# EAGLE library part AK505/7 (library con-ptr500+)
CONNECTOR

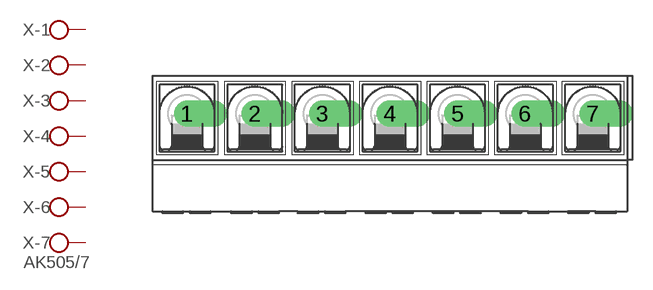
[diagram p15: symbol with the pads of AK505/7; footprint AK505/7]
Designator prefix X; gates -1=KL -2=KL -3=KL -4=KL -5=KL -6=KL -7=KLV

## AK505/7  [AK505/7]
1  -1:KL  pas
2  -2:KL  pas
3  -3:KL  pas
4  -4:KL  pas
5  -5:KL  pas
6  -6:KL  pas
7  -7:KL  pas

## Footprint AK505/7 (pad centres in mm)
CONNECTOR
drill 1.321 offset: 1 -15.037,0; 2 -10.008,0; 3 -5.004,0; 4 0,0; 5 5.004,0; 6 10.008,0; 7 15.037,0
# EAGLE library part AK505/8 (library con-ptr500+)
CONNECTOR

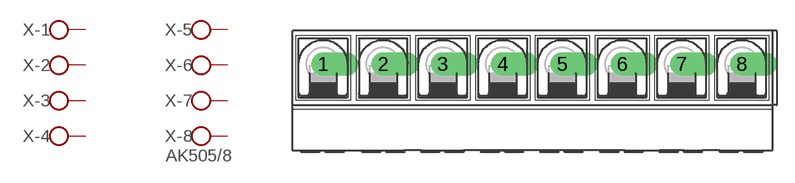
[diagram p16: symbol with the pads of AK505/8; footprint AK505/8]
Designator prefix X; gates -1=KL -2=KL -3=KL -4=KL -5=KL -6=KL -7=KL -8=KLV

## AK505/8  [AK505/8]
1  -1:KL  pas
2  -2:KL  pas
3  -3:KL  pas
4  -4:KL  pas
5  -5:KL  pas
6  -6:KL  pas
7  -7:KL  pas
8  -8:KL  pas

## Footprint AK505/8 (pad centres in mm)
CONNECTOR
drill 1.321 offset: 1 -17.526,0; 2 -12.497,0; 3 -7.518,0; 4 -2.489,0; 5 2.489,0; 6 7.518,0; 7 12.497,0; 8 17.526,0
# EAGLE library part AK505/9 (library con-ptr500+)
CONNECTOR

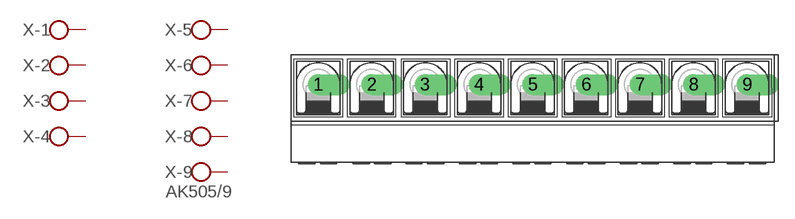
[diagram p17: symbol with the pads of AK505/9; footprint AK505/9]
Designator prefix X; gates -1=KL -2=KL -3=KL -4=KL -5=KL -6=KL -7=KL -8=KL -9=KLV

## AK505/9  [AK505/9]
1  -1:KL  pas
2  -2:KL  pas
3  -3:KL  pas
4  -4:KL  pas
5  -5:KL  pas
6  -6:KL  pas
7  -7:KL  pas
8  -8:KL  pas
9  -9:KL  pas

## Footprint AK505/9 (pad centres in mm)
CONNECTOR
drill 1.321 offset: 1 -20.015,0; 2 -15.011,0; 3 -10.033,0; 4 -5.004,0; 5 0,0; 6 5.004,0; 7 10.033,0; 8 15.011,0; 9 20.015,0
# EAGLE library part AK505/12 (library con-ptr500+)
CONNECTOR

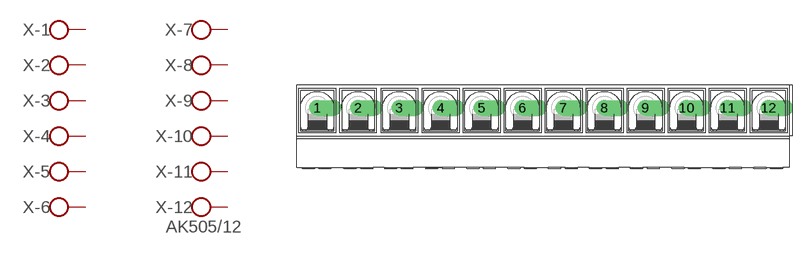
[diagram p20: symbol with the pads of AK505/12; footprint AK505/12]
Designator prefix X; gates -1=KL -2=KL -3=KL -4=KL -5=KL -6=KL -7=KL -8=KL -9=KL -10=KL -11=KL -12=KLV

## AK505/12  [AK505/12]
1  -1:KL  pas
2  -2:KL  pas
3  -3:KL  pas
4  -4:KL  pas
5  -5:KL  pas
6  -6:KL  pas
7  -7:KL  pas
8  -8:KL  pas
9  -9:KL  pas
10  -10:KL  pas
11  -11:KL  pas
12  -12:KL  pas

## Footprint AK505/12 (pad centres in mm)
CONNECTOR
drill 1.321 offset: 1 -27.534,0; 2 -22.53,0; 3 -17.526,0; 4 -12.497,0; 5 -7.493,0; 6 -2.489,0; 7 2.489,0; 8 7.493,0; 9 12.497,0; 10 17.526,0; 11 22.53,0; 12 27.534,0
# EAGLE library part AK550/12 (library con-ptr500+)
CONNECTOR

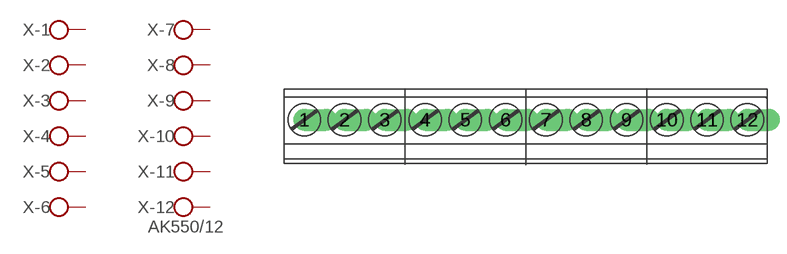
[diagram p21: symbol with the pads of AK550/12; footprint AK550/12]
Designator prefix X; gates -1=KL -2=KL -3=KL -4=KL -5=KL -6=KL -7=KL -8=KL -9=KL -10=KL -11=KL -12=KLV

## AK550/12  [AK550/12]
1  -1:KL  pas
2  -2:KL  pas
3  -3:KL  pas
4  -4:KL  pas
5  -5:KL  pas
6  -6:KL  pas
7  -7:KL  pas
8  -8:KL  pas
9  -9:KL  pas
10  -10:KL  pas
11  -11:KL  pas
12  -12:KL  pas

## Footprint AK550/12 (pad centres in mm)
CONNECTOR
drill 1.27 offset: 1 -19.25,0; 2 -15.75,0; 3 -12.25,0; 4 -8.75,0; 5 -5.25,0; 6 -1.75,0; 7 1.75,0; 8 5.25,0; 9 8.75,0; 10 12.25,0; 11 15.75,0; 12 19.25,0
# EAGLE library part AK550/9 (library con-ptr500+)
CONNECTOR

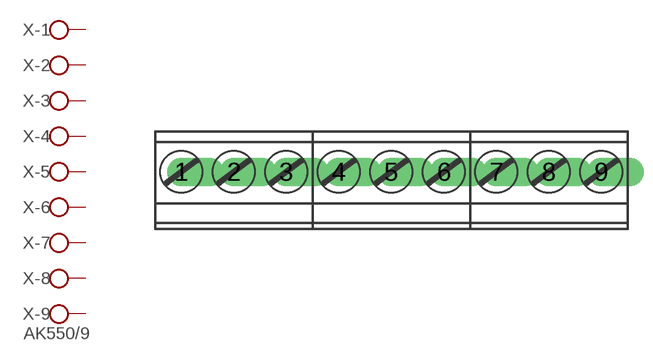
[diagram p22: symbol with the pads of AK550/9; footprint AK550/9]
Designator prefix X; gates -1=KL -2=KL -3=KL -4=KL -5=KL -6=KL -7=KL -8=KL -9=KLV

## AK550/9  [AK550/9]
1  -1:KL  pas
2  -2:KL  pas
3  -3:KL  pas
4  -4:KL  pas
5  -5:KL  pas
6  -6:KL  pas
7  -7:KL  pas
8  -8:KL  pas
9  -9:KL  pas

## Footprint AK550/9 (pad centres in mm)
CONNECTOR
drill 1.27 offset: 1 -14,0; 2 -10.5,0; 3 -7,0; 4 -3.5,0; 5 0,0; 6 3.5,0; 7 7,0; 8 10.5,0; 9 14,0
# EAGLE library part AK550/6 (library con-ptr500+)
CONNECTOR

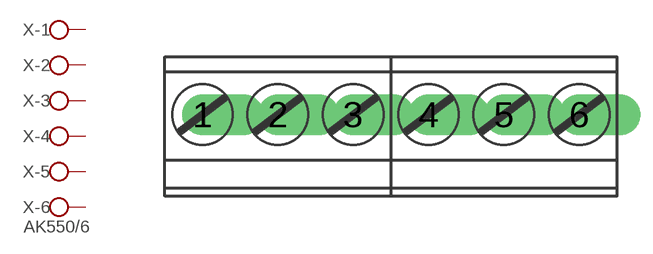
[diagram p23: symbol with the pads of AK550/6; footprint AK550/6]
Designator prefix X; gates -1=KL -2=KL -3=KL -4=KL -5=KL -6=KLV

## AK550/6  [AK550/6]
1  -1:KL  pas
2  -2:KL  pas
3  -3:KL  pas
4  -4:KL  pas
5  -5:KL  pas
6  -6:KL  pas

## Footprint AK550/6 (pad centres in mm)
CONNECTOR
drill 1.27 offset: 1 -8.75,0; 2 -5.25,0; 3 -1.75,0; 4 1.75,0; 5 5.25,0; 6 8.75,0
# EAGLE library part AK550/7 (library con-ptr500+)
CONNECTOR

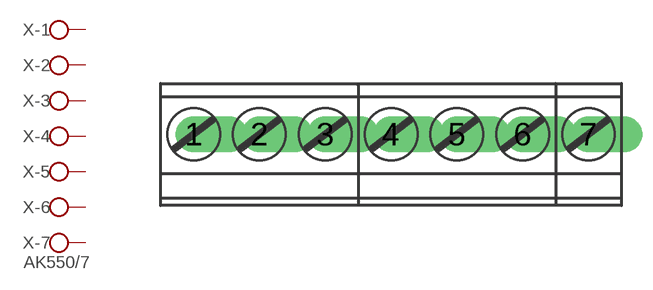
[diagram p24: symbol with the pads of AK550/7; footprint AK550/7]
Designator prefix X; gates -1=KL -2=KL -3=KL -4=KL -5=KL -6=KL -7=KLV

## AK550/7  [AK550/7]
1  -1:KL  pas
2  -2:KL  pas
3  -3:KL  pas
4  -4:KL  pas
5  -5:KL  pas
6  -6:KL  pas
7  -7:KL  pas

## Footprint AK550/7 (pad centres in mm)
CONNECTOR
drill 1.27 offset: 1 -10.5,0; 2 -7,0; 3 -3.5,0; 4 0,0; 5 3.5,0; 6 7,0; 7 10.5,0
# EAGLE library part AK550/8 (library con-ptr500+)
CONNECTOR

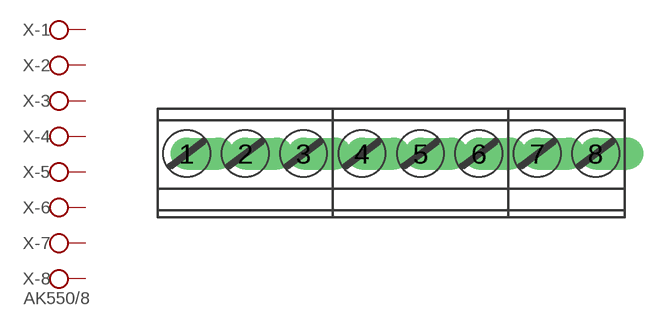
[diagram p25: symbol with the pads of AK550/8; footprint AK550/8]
Designator prefix X; gates -1=KL -2=KL -3=KL -4=KL -5=KL -6=KL -7=KL -8=KLV

## AK550/8  [AK550/8]
1  -1:KL  pas
2  -2:KL  pas
3  -3:KL  pas
4  -4:KL  pas
5  -5:KL  pas
6  -6:KL  pas
7  -7:KL  pas
8  -8:KL  pas

## Footprint AK550/8 (pad centres in mm)
CONNECTOR
drill 1.27 offset: 1 -12.25,0; 2 -8.75,0; 3 -5.25,0; 4 -1.75,0; 5 1.75,0; 6 5.25,0; 7 8.75,0; 8 12.25,0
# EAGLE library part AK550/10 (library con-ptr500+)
CONNECTOR

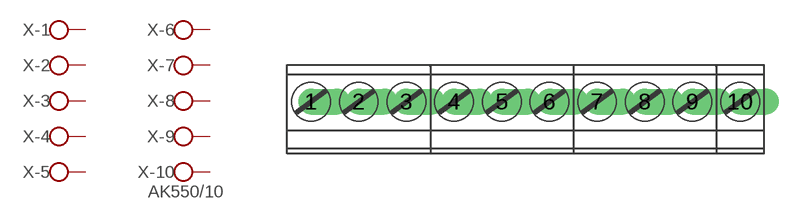
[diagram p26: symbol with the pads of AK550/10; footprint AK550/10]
Designator prefix X; gates -1=KL -2=KL -3=KL -4=KL -5=KL -6=KL -7=KL -8=KL -9=KL -10=KLV

## AK550/10  [AK550/10]
1  -1:KL  pas
2  -2:KL  pas
3  -3:KL  pas
4  -4:KL  pas
5  -5:KL  pas
6  -6:KL  pas
7  -7:KL  pas
8  -8:KL  pas
9  -9:KL  pas
10  -10:KL  pas

## Footprint AK550/10 (pad centres in mm)
CONNECTOR
drill 1.27 offset: 1 -15.75,0; 2 -12.25,0; 3 -8.75,0; 4 -5.25,0; 5 -1.75,0; 6 1.75,0; 7 5.25,0; 8 8.75,0; 9 12.25,0; 10 15.75,0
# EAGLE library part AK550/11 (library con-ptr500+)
CONNECTOR

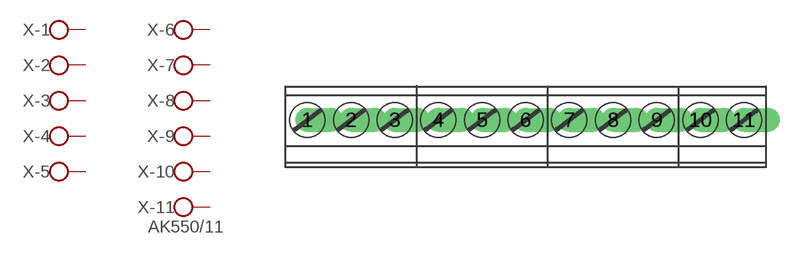
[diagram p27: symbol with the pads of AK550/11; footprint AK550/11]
Designator prefix X; gates -1=KL -2=KL -3=KL -4=KL -5=KL -6=KL -7=KL -8=KL -9=KL -10=KL -11=KLV

## AK550/11  [AK550/11]
1  -1:KL  pas
2  -2:KL  pas
3  -3:KL  pas
4  -4:KL  pas
5  -5:KL  pas
6  -6:KL  pas
7  -7:KL  pas
8  -8:KL  pas
9  -9:KL  pas
10  -10:KL  pas
11  -11:KL  pas

## Footprint AK550/11 (pad centres in mm)
CONNECTOR
drill 1.27 offset: 1 -17.5,0; 2 -14,0; 3 -10.5,0; 4 -7,0; 5 -3.5,0; 6 0,0; 7 3.5,0; 8 7,0; 9 10.5,0; 10 14,0; 11 17.5,0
